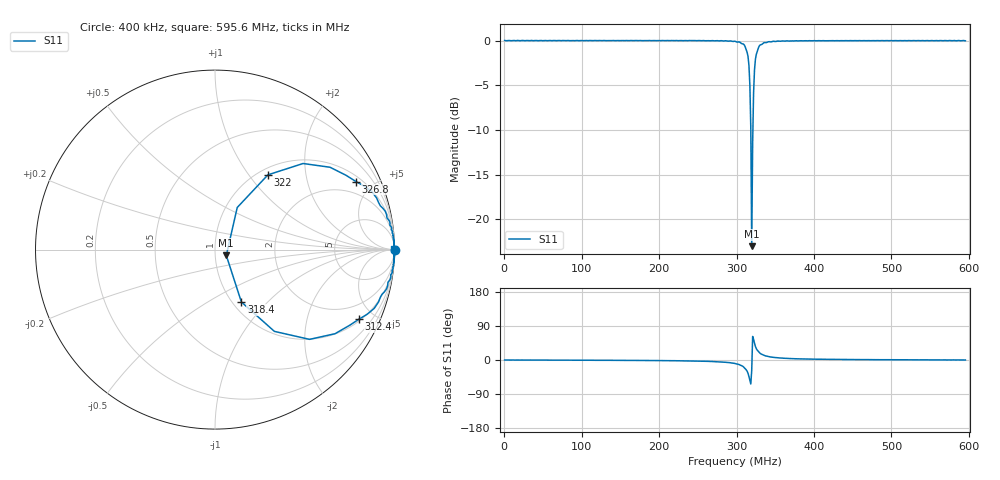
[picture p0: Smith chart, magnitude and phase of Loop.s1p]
! Generated by circuitRF - EM: openEMS
! circuitRF-EM setup: Loop OwnGrid
! circuitRF-EM layout: Loop.c3d
! circuitRF-EM written: 2026-10-18 18:25:07Z
! circuitRF-EM geometry: 7b4e7e1f99c8c731
! circuitRF-EM mesh: edaf1c1c067e6d77
! circuitRF-EM ports: e37d78baeb0ef280
! circuitRF-EM model: openEMS 0.37.0 (v0.37.0, CSXCAD v0.7.0)
! circuitRF-EM port 1: 'port/1' from 'bottomLeft' to 'bottomRight', lumped, 2.5 Ohm
! circuitRF-EM 3D grid: 138 x 120 x 142 = 2351520 cells; smallest cell 1.6667 mm on y, set by 'capLeft' port extent at y = -28.3333 mm; 'capLeft' port extent at y = -26.6667 mm; 'bottomLeft' edge at y = -833.333 um; 'topLeft' edge at y = -833.333 um; 'port/1' port extent at y = -833.333 um; 'capTop'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
! circuitRF-EM 3D openEMS run port 1: dt 3.47935E-12 s (estimate 3.36536E-12 s), 50640 steps, port signals 32.1 dB and energy 40.2 dB against 40 dB, stopped by openEMS's energy criterion, converged
! circuitRF-EM 3D dielectric loss fitted at: 0.298 GHz
! circuitRF-EM 3D perfect conductors: bottomLeft, topLeft, bottomRight, topRight, leftLower, leftUpper, rightLower, rightUpper
! circuitRF-EM 3D operating temperature: 20 C
! circuitRF-EM: re-running the EM setup rewrites this file. If circuitRF reports it as stale, the layout's cross-section changed after this file was written.
# MHz S RI R 2.5
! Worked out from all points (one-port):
!   497 points, 400 kHz to 595.6 MHz, reference 2.5 ohm
!   lowest |S11| = -23.0 dB at 319.6 MHz (marker M1), VSWR 1.15, Z = 2.83 - j0.184 ohm
!   |S11| at or under -10 dB: 318.4 MHz to 321.1 MHz (2.696 MHz wide, 0.843 % of centre)
!   S11 on the Smith chart (normalised r, x): 400 kHz: open; 312.4 MHz: 1.09, -4.10; 318.4 MHz: 1.10, -0.72; 322 MHz: 1.10, +1.24; 326.8 MHz: 1.26, +3.99; 595.6 MHz: open
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0.4  1.002 -0.000772
74.8  1 -0.00602
149.2  0.999 -0.0164
223.6  0.9989 -0.0363
274  0.9963 -0.0768
298  0.9783 -0.1612
307.6  0.9214 -0.2653
310  0.8871 -0.3275
312.4  0.8025 -0.3874
313.6  0.7505 -0.4215
314.8  0.6686 -0.4686
316  0.5267 -0.5001
317.2  0.3312 -0.4557
318.4  0.147 -0.2919
319.6  0.0629 -0.0324
320.8  0.1239 0.2346
322  0.2949 0.4165
323.2  0.4907 0.4797
324.4  0.641 0.4588
325.6  0.7304 0.4138
326.8  0.7851 0.3794
330.4  0.8996 0.289
337.6  0.9572 0.182
350.8  0.9828 0.1093
372.4  0.994 0.0614
446.8  0.9994 0.0214
521.2  0.9992 0.00979
595.6  0.9973 0.00166
